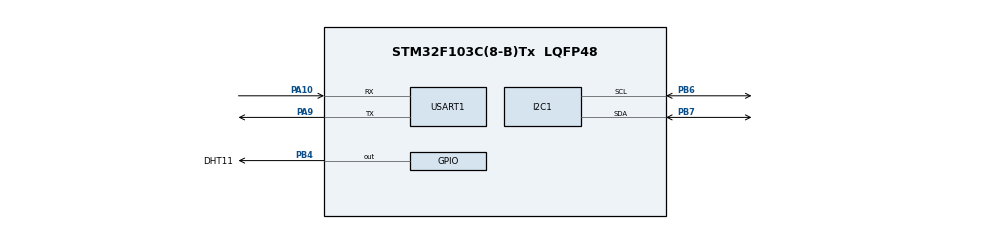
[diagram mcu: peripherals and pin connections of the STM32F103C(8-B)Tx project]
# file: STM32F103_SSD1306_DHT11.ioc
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Mcu.Family=STM32F1
Mcu.Name=STM32F103C(8-B)Tx
Mcu.Package=LQFP48
NVIC.PriorityGroup=NVIC_PRIORITYGROUP_4
PA10.Mode=Asynchronous
PA10.Signal=USART1_RX
PA9.Mode=Asynchronous
PA9.Signal=USART1_TX
PB4.GPIO_Label=DHT11
PB4.GPIO_Speed=GPIO_SPEED_FREQ_HIGH
PB4.PinState=GPIO_PIN_RESET
PB4.Signal=GPIO_Output
PB6.Mode=I2C
PB6.Signal=I2C1_SCL
PB7.Mode=I2C
PB7.Signal=I2C1_SDA
PD0-OSC_IN.Mode=HSE-External-Oscillator
PD0-OSC_IN.Signal=RCC_OSC_IN
PD1-OSC_OUT.Mode=HSE-External-Oscillator
PD1-OSC_OUT.Signal=RCC_OSC_OUT
ProjectManager.HeapSize=0x200
ProjectManager.StackSize=0x400
ProjectManager.TargetToolchain=MDK-ARM V5
RCC.AHBFreq_Value=32000000
RCC.APB1Freq_Value=32000000
RCC.APB1TimFreq_Value=32000000
RCC.APB2Freq_Value=32000000
RCC.APB2TimFreq_Value=32000000
RCC.HCLKFreq_Value=32000000
RCC.PLLMUL=RCC_PLL_MUL8
RCC.SYSCLKFreq_VALUE=32000000
RCC.SYSCLKSource=RCC_SYSCLKSOURCE_PLLCLK
RCC.USBFreq_Value=32000000
USART1.VirtualMode=VM_ASYNC
VP_SYS_VS_ND.Mode=No_Debug
board=STM32F103_SSD1306_DHT11

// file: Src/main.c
/**
  ******************************************************************************
  * File Name          : main.c
  * Description        : Main program body
  ******************************************************************************
  ** This notice applies to any and all portions of this file
  * that are not between comment pairs USER CODE BEGIN and
  * USER CODE END. Other portions of this file, whether
  * inserted by the user or by software development tools
  * are owned by their respective copyright owners.
  *
  * COPYRIGHT(c) 2018 STMicroelectronics
  *
  * Redistribution and use in source and binary forms, with or without modification,
  * are permitted provided that the following conditions are met:
  *   1. Redistributions of source code must retain the above copyright notice,
  *      this list of conditions and the following disclaimer.
  *   2. Redistributions in binary form must reproduce the above copyright notice,
  *      this list of conditions and the following disclaimer in the documentation
  *      and/or other materials provided with the distribution.
  *   3. Neither the name of STMicroelectronics nor the names of its contributors
  *      may be used to endorse or promote products derived from this software
  *      without specific prior written permission.
  *
  * THIS SOFTWARE IS PROVIDED BY THE COPYRIGHT HOLDERS AND CONTRIBUTORS "AS IS"
  * AND ANY EXPRESS OR IMPLIED WARRANTIES, INCLUDING, BUT NOT LIMITED TO, THE
  * IMPLIED WARRANTIES OF MERCHANTABILITY AND FITNESS FOR A PARTICULAR PURPOSE ARE
  * DISCLAIMED. IN NO EVENT SHALL THE COPYRIGHT HOLDER OR CONTRIBUTORS BE LIABLE
  * FOR ANY DIRECT, INDIRECT, INCIDENTAL, SPECIAL, EXEMPLARY, OR CONSEQUENTIAL
  * DAMAGES (INCLUDING, BUT NOT LIMITED TO, PROCUREMENT OF SUBSTITUTE GOODS OR
  * SERVICES; LOSS OF USE, DATA, OR PROFITS; OR BUSINESS INTERRUPTION) HOWEVER
  * CAUSED AND ON ANY THEORY OF LIABILITY, WHETHER IN CONTRACT, STRICT LIABILITY,
  * OR TORT (INCLUDING NEGLIGENCE OR OTHERWISE) ARISING IN ANY WAY OUT OF THE USE
  * OF THIS SOFTWARE, EVEN IF ADVISED OF THE POSSIBILITY OF SUCH DAMAGE.
  *
  ******************************************************************************
  */

#include "main.h"
#include "stm32f1xx_hal.h"

/* USER CODE BEGIN Includes */
#include "delay.h"
#include "dht11.h"
#include "ssd1306.h"
#include "usart.h"

/* USER CODE END Includes */

I2C_HandleTypeDef hi2c1;
DHT11_ReadTypeDef DHT11;

/* USER CODE BEGIN PV */
/* Private variables ---------------------------------------------------------*/

/* USER CODE END PV */

void SystemClock_Config(void);
static void MX_GPIO_Init(void);
static void MX_I2C1_Init(void);

/* USER CODE BEGIN PFP */
/* Private function prototypes -----------------------------------------------*/

/* USER CODE END PFP */

int main(void)
{

  /* MCU Configuration----------------------------------------------------------*/

  /* Reset of all peripherals, Initializes the Flash interface and the Systick. */
  HAL_Init();

  /* Configure the system clock */
  SystemClock_Config();

  /* Initialize all configured peripherals */
  MX_GPIO_Init();
  MX_I2C1_Init();
  MX_USART1_UART_Init();
  Delay_Init(32);
  SSD1306_Init();
  DHT11_Init();

  char buf[25];

  /* USER CODE BEGIN 2 */
  SSD1306_GotoXY(15,20);
  SSD1306_Puts("system start...", &Font_7x10, SSD1306_COLOR_WHITE);
  SSD1306_UpdateScreen();
  Delay_ms(1000);
  SSD1306_GotoXY(15,45);
  SSD1306_Puts("www.imliubo.me", &Font_7x10, SSD1306_COLOR_WHITE);
  SSD1306_UpdateScreen();
  Delay_ms(2000);

  /* USER CODE END 2 */

  /* Infinite loop */
  while (1)
  {

  /* USER CODE BEGIN 3 */
  //		printf("read data!\r\n");
     DHT11_Read_Data(&DHT11);
     printf("TEMP: %d HUMD: %d\r\n",DHT11.Temperature,DHT11.Humidity);
     sprintf(buf, "TEMP: %d HUMD: %d",DHT11.Temperature,DHT11.Humidity);
     SSD1306_Fill(SSD1306_COLOR_BLACK);
     SSD1306_GotoXY(2,20);
     SSD1306_Puts(buf, &Font_7x10, SSD1306_COLOR_WHITE);
     SSD1306_GotoXY(15,40);
     SSD1306_Puts("www.imliubo.me", &Font_7x10, SSD1306_COLOR_WHITE);
     SSD1306_UpdateScreen();
     Delay_ms(3000);

  }
  /* USER CODE END 3 */

}

/** System Clock Configuration
*/
void SystemClock_Config(void)
{

  RCC_OscInitTypeDef RCC_OscInitStruct;
  RCC_ClkInitTypeDef RCC_ClkInitStruct;

    /**Initializes the CPU, AHB and APB busses clocks
    */
  RCC_OscInitStruct.OscillatorType = RCC_OSCILLATORTYPE_HSE;
  RCC_OscInitStruct.HSEState = RCC_HSE_ON;
  RCC_OscInitStruct.HSEPredivValue = RCC_HSE_PREDIV_DIV1;
  RCC_OscInitStruct.HSIState = RCC_HSI_ON;
  RCC_OscInitStruct.PLL.PLLState = RCC_PLL_ON;
  RCC_OscInitStruct.PLL.PLLSource = RCC_PLLSOURCE_HSE;
  RCC_OscInitStruct.PLL.PLLMUL = RCC_PLL_MUL4;
  if (HAL_RCC_OscConfig(&RCC_OscInitStruct) != HAL_OK)
  {
    _Error_Handler(__FILE__, __LINE__);
  }

    /**Initializes the CPU, AHB and APB busses clocks
    */
  RCC_ClkInitStruct.ClockType = RCC_CLOCKTYPE_HCLK|RCC_CLOCKTYPE_SYSCLK
                              |RCC_CLOCKTYPE_PCLK1|RCC_CLOCKTYPE_PCLK2;
  RCC_ClkInitStruct.SYSCLKSource = RCC_SYSCLKSOURCE_PLLCLK;
  RCC_ClkInitStruct.AHBCLKDivider = RCC_SYSCLK_DIV1;
  RCC_ClkInitStruct.APB1CLKDivider = RCC_HCLK_DIV2;
  RCC_ClkInitStruct.APB2CLKDivider = RCC_HCLK_DIV1;

  if (HAL_RCC_ClockConfig(&RCC_ClkInitStruct, FLASH_LATENCY_1) != HAL_OK)
  {
    _Error_Handler(__FILE__, __LINE__);
  }

    /**Configure the Systick interrupt time
    */
  HAL_SYSTICK_Config(HAL_RCC_GetHCLKFreq()/1000);

    /**Configure the Systick
    */
  HAL_SYSTICK_CLKSourceConfig(SYSTICK_CLKSOURCE_HCLK);

  /* SysTick_IRQn interrupt configuration */
  HAL_NVIC_SetPriority(SysTick_IRQn, 0, 0);
}

/* I2C1 init function */
static void MX_I2C1_Init(void)
{

  hi2c1.Instance = I2C1;
  hi2c1.Init.ClockSpeed = 400000;
  hi2c1.Init.DutyCycle = I2C_DUTYCYCLE_2;
  hi2c1.Init.OwnAddress1 = 0;
  hi2c1.Init.AddressingMode = I2C_ADDRESSINGMODE_7BIT;
  hi2c1.Init.DualAddressMode = I2C_DUALADDRESS_DISABLE;
  hi2c1.Init.OwnAddress2 = 0;
  hi2c1.Init.GeneralCallMode = I2C_GENERALCALL_DISABLE;
  hi2c1.Init.NoStretchMode = I2C_NOSTRETCH_DISABLE;
  if (HAL_I2C_Init(&hi2c1) != HAL_OK)
  {
    _Error_Handler(__FILE__, __LINE__);
  }

}

/* USART1 init function */

/** Configure pins as
        * Analog
        * Input
        * Output
        * EVENT_OUT
        * EXTI
*/
static void MX_GPIO_Init(void)
{

  GPIO_InitTypeDef GPIO_InitStruct;

  /* GPIO Ports Clock Enable */
  __HAL_RCC_GPIOD_CLK_ENABLE();
  __HAL_RCC_GPIOA_CLK_ENABLE();
  __HAL_RCC_GPIOB_CLK_ENABLE();

  /*Configure GPIO pin Output Level */
  HAL_GPIO_WritePin(DHT11_GPIO_Port, DHT11_Pin, GPIO_PIN_RESET);

  /*Configure GPIO pin : DHT11_Pin */
  GPIO_InitStruct.Pin = DHT11_Pin;
  GPIO_InitStruct.Mode = GPIO_MODE_OUTPUT_PP;
  GPIO_InitStruct.Speed = GPIO_SPEED_FREQ_HIGH;
  HAL_GPIO_Init(DHT11_GPIO_Port, &GPIO_InitStruct);

}

void _Error_Handler(char * file, int line)
{
  while(1)
  {
  }
}

/************************ (C) COPYRIGHT STMicroelectronics *****END OF FILE****/
